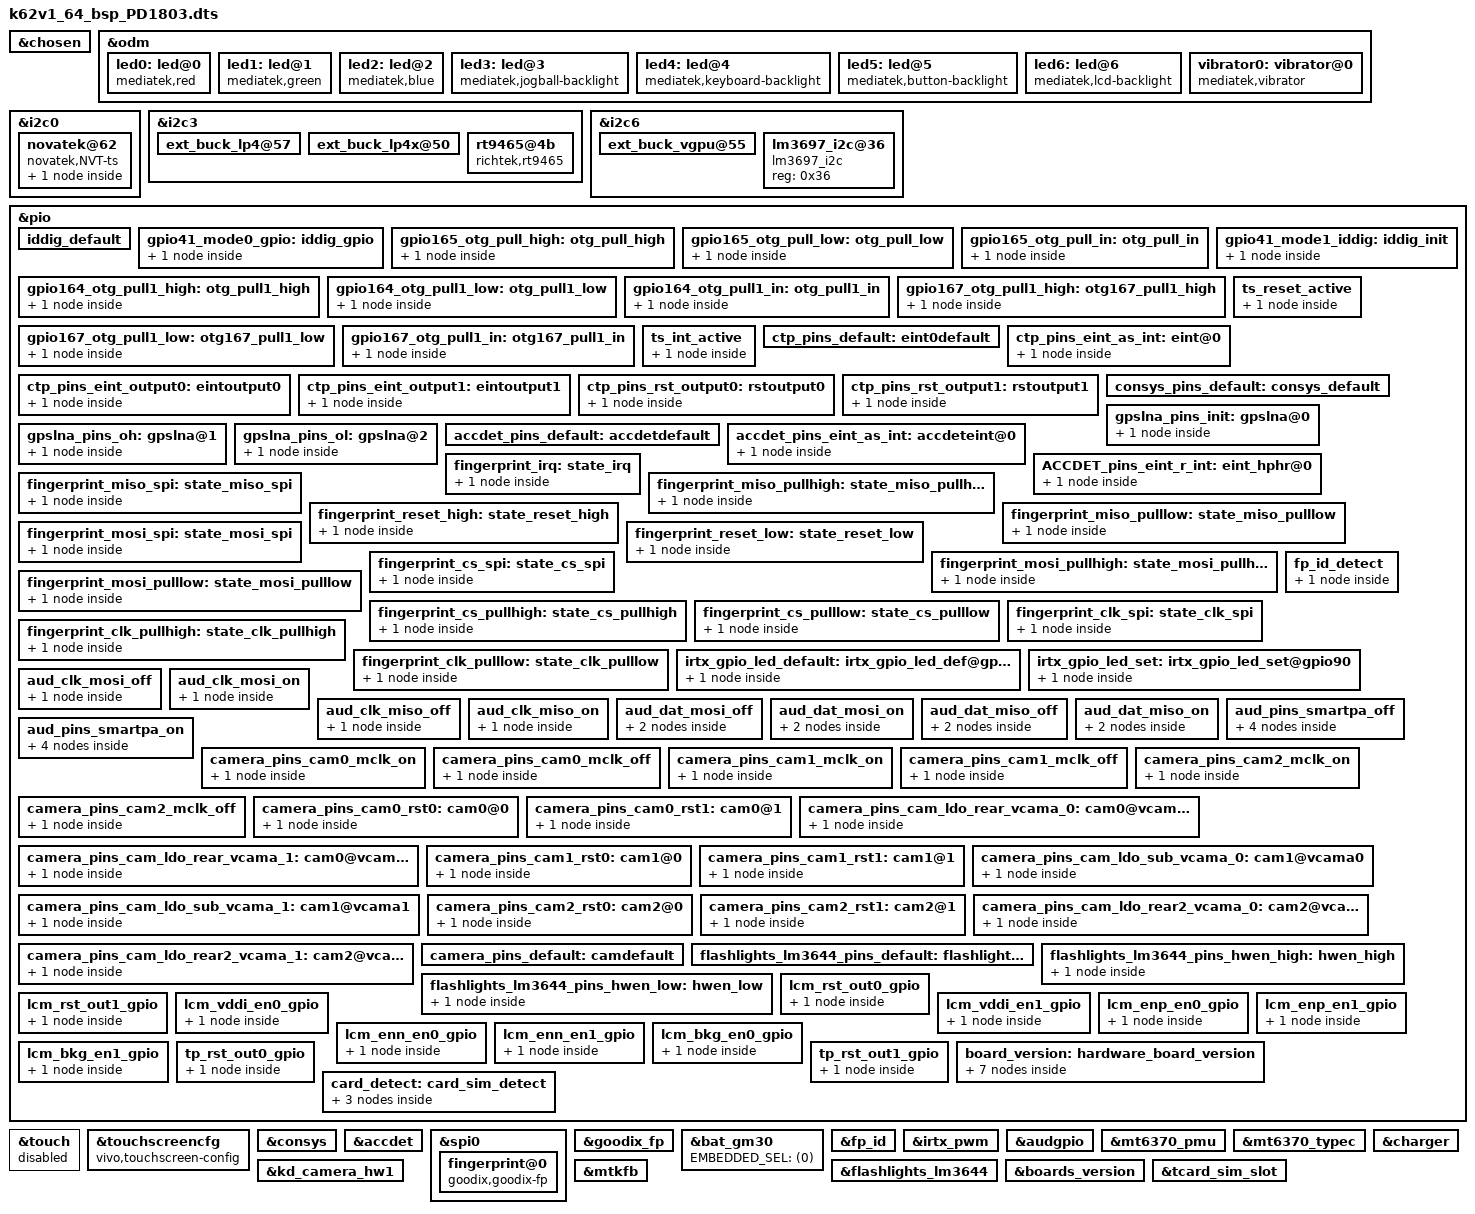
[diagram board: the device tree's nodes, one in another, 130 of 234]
#include <dt-bindings/interrupt-controller/arm-gic.h>
#include <dt-bindings/interrupt-controller/irq.h>
#include <dt-bindings/pinctrl/mt6765-pinfunc.h>
#include <dt-bindings/clock/mt6765-clk.h>

/dts-v1/;
/plugin/;

/* chosen */
&chosen {
	bootargs = "console=tty0 console=ttyS0,921600n1\
root=/dev/ram initrd=0x45000000,0x1000000 loglevel=8 \
androidboot.selinux=permissive androidboot.hardware=mt6765 \
initcall_debug=1 maxcpus=1";

	/* fpga may has no lk, we need to specify display info here */
	/* fb buffer is reserved using this dts by memory node above */
	atag,videolfb-fb_base_h = <0x0>;
	atag,videolfb-fb_base_l = <0x5e605000>;
	atag,videolfb-islcmfound = <1>;
	/* because no lk, so lcm is not inited */
	atag,videolfb-islcm_inited = <0>;
	atag,videolfb-fps= <6000>;
	atag,videolfb-vramSize= <0x017bb000>;
	atag,videolfb-lcmname= "nt35695B_fhd_dsi_cmd_auo_rt5081_drv";
	atag,videolfb-project-name= "PD1803";
};

&odm {
	led0:led@0 {
		compatible = "mediatek,red";
		led_mode = <0>;
		data = <1>;
		pwm_config = <0 0 0 0 0>;
	};
	led1:led@1 {
		compatible = "mediatek,green";
		led_mode = <0>;
		data = <1>;
		pwm_config = <0 0 0 0 0>;
	};
	led2:led@2 {
		compatible = "mediatek,blue";
		led_mode = <0>;
		data = <1>;
		pwm_config = <0 0 0 0 0>;
	};
	led3:led@3 {
		compatible = "mediatek,jogball-backlight";
		led_mode = <0>;
		data = <1>;
		pwm_config = <0 0 0 0 0>;
	};
	led4:led@4 {
		compatible = "mediatek,keyboard-backlight";
		led_mode = <0>;
		data = <1>;
		pwm_config = <0 0 0 0 0>;
	};
	led5:led@5 {
		compatible = "mediatek,button-backlight";
		led_mode = <0>;
		data = <1>;
		pwm_config = <0 0 0 0 0>;
	};
	led6:led@6 {
		compatible = "mediatek,lcd-backlight";
		led_mode = <4>;
		data = <1>;
		pwm_config = <0 0 0 0 0>;
	};
	vibrator0:vibrator@0 {
		compatible = "mediatek,vibrator";
		vib_timer = <25>;
		vib_limit = <9>;
		vib_vol= <9>;
	};
};

&i2c0 {
/*	focaltech@38{ 
	compatible = "focaltech_8006m,fts_8006m";	
	reg = <0x38>;  					
	interrupt-parent = <&pio>;				
	interrupts = <65 0x02>;
	pinctrl-names ="default";
	pinctrl-0 = <&ts_reset_active &ts_int_active>;
//	focaltech,reset-gpio = <&pio 64 0x01>; 
	focaltech,irq-gpio = <&pio 0 0x02>; 	

	focaltech,max-touch-number = <10>;			
	focaltech,display-coords =  <0 0 1080 1920>;	 

//	focaltech,have-key;
	focaltech,key-number = <3>;	
	focaltech,keys = <139 102 158>; 	
	focaltech,key-y-coord = <2000>; 
	focaltech,key-x-coords = <200 600 800>;
};
*/
	novatek@62 {
		compatible = "novatek,NVT-ts";
		reg = <0x62>;
		status = "ok";
		//vdd-supply = <&pm8994_lvs2>;    //VDDIO
		//avdd-supply = <&pm8994_l22>;    //VDD
		//novatek,reset-gpio = <&msm_gpio 102 0x00>;
		novatek,irq-gpio = <&pio 0 0x02>;
		/* MP */
		novatek,mp-support-dt;

		novatek-mp-criteria-5B09@0 {
			#address-cells = <1>;
			#size-cells = <0>;
			compatible = "novatek-mp-criteria-5B09";

			/* MP Config */
			IC_X_CFG_SIZE = <18>;
			IC_Y_CFG_SIZE = <32>;
			IC_KEY_CFG_SIZE = <4>;
			X_Channel = <18>;
			Y_Channel = <32>;
			AIN_X = <0 1 2 3 4 5 6 7 8 9 10 11 12 13 14 15 16 17>;
			AIN_Y = <0 1 2 3 4 5 6 7 8 9 10 11 12 13 14 15 16 17 18 19 20 21 22 23 24 25 26 27 28 29 30 31>;

			AIN_KEY = <0 1 2 0xFF>;
			/* MP Criteria */
			PS_Config_Lmt_Short_Rawdata_P = <
				14008 14008 14008 14008 14008 14008 14008 14008 14008 14008 14008 14008 14008 14008 14008 14008 14008 14008
				14008 14008 14008 14008 14008 14008 14008 14008 14008 14008 14008 14008 14008 14008 14008 14008 14008 14008
				14008 14008 14008 14008 14008 14008 14008 14008 14008 14008 14008 14008 14008 14008 14008 14008 14008 14008
				14008 14008 14008 14008 14008 14008 14008 14008 14008 14008 14008 14008 14008 14008 14008 14008 14008 14008
				14008 14008 14008 14008 14008 14008 14008 14008 14008 14008 14008 14008 14008 14008 14008 14008 14008 14008
				14008 14008 14008 14008 14008 14008 14008 14008 14008 14008 14008 14008 14008 14008 14008 14008 14008 14008
				14008 14008 14008 14008 14008 14008 14008 14008 14008 14008 14008 14008 14008 14008 14008 14008 14008 14008
				14008 14008 14008 14008 14008 14008 14008 14008 14008 14008 14008 14008 14008 14008 14008 14008 14008 14008
				14008 14008 14008 14008 14008 14008 14008 14008 14008 14008 14008 14008 14008 14008 14008 14008 14008 14008
				14008 14008 14008 14008 14008 14008 14008 14008 14008 14008 14008 14008 14008 14008 14008 14008 14008 14008
				14008 14008 14008 14008 14008 14008 14008 14008 14008 14008 14008 14008 14008 14008 14008 14008 14008 14008
				14008 14008 14008 14008 14008 14008 14008 14008 14008 14008 14008 14008 14008 14008 14008 14008 14008 14008
				14008 14008 14008 14008 14008 14008 14008 14008 14008 14008 14008 14008 14008 14008 14008 14008 14008 14008
				14008 14008 14008 14008 14008 14008 14008 14008 14008 14008 14008 14008 14008 14008 14008 14008 14008 14008
				14008 14008 14008 14008 14008 14008 14008 14008 14008 14008 14008 14008 14008 14008 14008 14008 14008 14008
				14008 14008 14008 14008 14008 14008 14008 14008 14008 14008 14008 14008 14008 14008 14008 14008 14008 14008
				14008 14008 14008 14008 14008 14008 14008 14008 14008 14008 14008 14008 14008 14008 14008 14008 14008 14008
				14008 14008 14008 14008 14008 14008 14008 14008 14008 14008 14008 14008 14008 14008 14008 14008 14008 14008
				14008 14008 14008 14008 14008 14008 14008 14008 14008 14008 14008 14008 14008 14008 14008 14008 14008 14008
				14008 14008 14008 14008 14008 14008 14008 14008 14008 14008 14008 14008 14008 14008 14008 14008 14008 14008
				14008 14008 14008 14008 14008 14008 14008 14008 14008 14008 14008 14008 14008 14008 14008 14008 14008 14008
				14008 14008 14008 14008 14008 14008 14008 14008 14008 14008 14008 14008 14008 14008 14008 14008 14008 14008
				14008 14008 14008 14008 14008 14008 14008 14008 14008 14008 14008 14008 14008 14008 14008 14008 14008 14008
				14008 14008 14008 14008 14008 14008 14008 14008 14008 14008 14008 14008 14008 14008 14008 14008 14008 14008
				14008 14008 14008 14008 14008 14008 14008 14008 14008 14008 14008 14008 14008 14008 14008 14008 14008 14008
				14008 14008 14008 14008 14008 14008 14008 14008 14008 14008 14008 14008 14008 14008 14008 14008 14008 14008
				14008 14008 14008 14008 14008 14008 14008 14008 14008 14008 14008 14008 14008 14008 14008 14008 14008 14008
				14008 14008 14008 14008 14008 14008 14008 14008 14008 14008 14008 14008 14008 14008 14008 14008 14008 14008
				14008 14008 14008 14008 14008 14008 14008 14008 14008 14008 14008 14008 14008 14008 14008 14008 14008 14008
				14008 14008 14008 14008 14008 14008 14008 14008 14008 14008 14008 14008 14008 14008 14008 14008 14008 14008
				14008 14008 14008 14008 14008 14008 14008 14008 14008 14008 14008 14008 14008 14008 14008 14008 14008 14008
				14008 14008 14008 14008 14008 14008 14008 14008 14008 14008 14008 14008 14008 14008 14008 14008 14008 14008
				>;

			PS_Config_Lmt_Short_Rawdata_N = <
				11376 11376 11376 11376 11376 11376 11376 11376 11376 11376 11376 11376 11376 11376 11376 11376 11376 11376
				11376 11376 11376 11376 11376 11376 11376 11376 11376 11376 11376 11376 11376 11376 11376 11376 11376 11376
				11376 11376 11376 11376 11376 11376 11376 11376 11376 11376 11376 11376 11376 11376 11376 11376 11376 11376
				11376 11376 11376 11376 11376 11376 11376 11376 11376 11376 11376 11376 11376 11376 11376 11376 11376 11376
				11376 11376 11376 11376 11376 11376 11376 11376 11376 11376 11376 11376 11376 11376 11376 11376 11376 11376
				11376 11376 11376 11376 11376 11376 11376 11376 11376 11376 11376 11376 11376 11376 11376 11376 11376 11376
				11376 11376 11376 11376 11376 11376 11376 11376 11376 11376 11376 11376 11376 11376 11376 11376 11376 11376
				11376 11376 11376 11376 11376 11376 11376 11376 11376 11376 11376 11376 11376 11376 11376 11376 11376 11376
				11376 11376 11376 11376 11376 11376 11376 11376 11376 11376 11376 11376 11376 11376 11376 11376 11376 11376
				11376 11376 11376 11376 11376 11376 11376 11376 11376 11376 11376 11376 11376 11376 11376 11376 11376 11376
				11376 11376 11376 11376 11376 11376 11376 11376 11376 11376 11376 11376 11376 11376 11376 11376 11376 11376
				11376 11376 11376 11376 11376 11376 11376 11376 11376 11376 11376 11376 11376 11376 11376 11376 11376 11376
				11376 11376 11376 11376 11376 11376 11376 11376 11376 11376 11376 11376 11376 11376 11376 11376 11376 11376
				11376 11376 11376 11376 11376 11376 11376 11376 11376 11376 11376 11376 11376 11376 11376 11376 11376 11376
				11376 11376 11376 11376 11376 11376 11376 11376 11376 11376 11376 11376 11376 11376 11376 11376 11376 11376
				11376 11376 11376 11376 11376 11376 11376 11376 11376 11376 11376 11376 11376 11376 11376 11376 11376 11376
				11376 11376 11376 11376 11376 11376 11376 11376 11376 11376 11376 11376 11376 11376 11376 11376 11376 11376
				11376 11376 11376 11376 11376 11376 11376 11376 11376 11376 11376 11376 11376 11376 11376 11376 11376 11376
				11376 11376 11376 11376 11376 11376 11376 11376 11376 11376 11376 11376 11376 11376 11376 11376 11376 11376
				11376 11376 11376 11376 11376 11376 11376 11376 11376 11376 11376 11376 11376 11376 11376 11376 11376 11376
				11376 11376 11376 11376 11376 11376 11376 11376 11376 11376 11376 11376 11376 11376 11376 11376 11376 11376
				11376 11376 11376 11376 11376 11376 11376 11376 11376 11376 11376 11376 11376 11376 11376 11376 11376 11376
				11376 11376 11376 11376 11376 11376 11376 11376 11376 11376 11376 11376 11376 11376 11376 11376 11376 11376
				11376 11376 11376 11376 11376 11376 11376 11376 11376 11376 11376 11376 11376 11376 11376 11376 11376 11376
				11376 11376 11376 11376 11376 11376 11376 11376 11376 11376 11376 11376 11376 11376 11376 11376 11376 11376
				11376 11376 11376 11376 11376 11376 11376 11376 11376 11376 11376 11376 11376 11376 11376 11376 11376 11376
				11376 11376 11376 11376 11376 11376 11376 11376 11376 11376 11376 11376 11376 11376 11376 11376 11376 11376
				11376 11376 11376 11376 11376 11376 11376 11376 11376 11376 11376 11376 11376 11376 11376 11376 11376 11376
				11376 11376 11376 11376 11376 11376 11376 11376 11376 11376 11376 11376 11376 11376 11376 11376 11376 11376
				11376 11376 11376 11376 11376 11376 11376 11376 11376 11376 11376 11376 11376 11376 11376 11376 11376 11376
				11376 11376 11376 11376 11376 11376 11376 11376 11376 11376 11376 11376 11376 11376 11376 11376 11376 11376
				11376 11376 11376 11376 11376 11376 11376 11376 11376 11376 11376 11376 11376 11376 11376 11376 11376 11376
                >;

			

			PS_Config_Lmt_Open_Rawdata_P = <
				65536 3324 3384 3190 3071 2918 65536 65536 65536 65536 65536 65536 2957 3115 3234 3420 3377 65536
                2093 2002 2009 1971 1978 1959 1997 1939 2003 2033 1972 2032 1996 2013 2007 2041 2035 2139
                2077 1994 2000 1973 1979 1970 2006 2005 2063 2099 2043 2045 2010 2017 2011 2035 2031 2116
                2041 1956 1962 1935 1941 1932 1969 1965 2023 2064 2009 2010 1975 1983 1977 2001 1995 2080
                2070 1983 1989 1962 1968 1959 1997 1888 1947 2090 2034 2036 2000 2009 2002 2027 1915 2005
                2072 1984 1991 1964 1970 1959 1997 1996 2055 2088 2032 2033 1997 2006 2000 2026 2021 2110
                2047 1960 1966 1939 1945 1897 1934 1972 2030 2065 2011 2012 1976 1985 1942 1968 2003 2091
                2046 1957 1963 1936 1942 1859 1897 1970 2028 2061 2006 2007 1971 1981 1903 1930 1999 2088
                2083 1995 1998 1972 1976 1968 2005 2008 2065 2092 2036 2037 1999 2010 2006 2032 2028 2120
                2083 1993 1997 1864 1870 1968 2004 2007 2063 2096 2040 2041 1893 1906 2011 2037 2033 2125
                2053 1964 1968 1941 1945 1939 1974 1976 2032 2064 2010 2011 1973 1982 1982 2007 2004 2094
                2059 1968 1972 1949 1953 1944 1979 1981 2038 2065 2009 2011 1976 1986 1983 2008 2005 2096
                2089 1887 1893 1978 1981 1972 2008 2011 2067 2102 1932 1937 2011 2021 2019 2045 2042 2134
                2098 2005 2009 1986 1989 1980 2016 2019 2076 2102 2044 2046 2010 2021 2018 2045 2042 2135
                2062 1973 1977 1952 1955 1945 1981 1984 2040 2076 2023 2024 1986 1998 1995 2022 2020 2112
                1950 1973 1977 1952 1955 1945 1982 1984 2040 1958 2018 2020 1982 1993 1992 2018 2016 2108
                2066 1977 1980 1956 1959 1950 1986 1988 2044 2074 2019 2020 1983 1994 1993 2020 2018 2111
                2075 1987 1986 1963 1966 1957 1993 1994 2051 2080 2023 2025 1988 2000 1998 2025 2026 2117
                2105 2022 2014 1990 1994 1983 2021 1977 2034 2111 2055 2057 2018 2030 2029 2056 2020 2104
                2107 2023 2016 1992 1996 1986 2023 2024 2082 2113 2057 2059 2020 2032 2031 2058 2068 2154
                2070 1989 1980 1958 1961 1950 1988 1989 2046 2081 2025 2027 1989 2002 1999 2025 2037 2121
                2078 1996 1991 1964 1968 1911 1950 1997 2053 2081 2025 2028 1989 2002 1953 1983 2036 2121
                2115 2031 2033 2002 2003 1992 2031 2031 2090 2119 2062 2065 2025 2037 2039 2074 2073 2160
                2117 2033 2036 2011 2003 1993 2033 2033 2092 2123 2065 2070 2028 2041 2051 2079 2077 2164
                2084 2002 2005 1936 1929 1964 2002 2002 2059 2090 2034 2039 1951 1967 2020 2048 2044 2132
                2085 2003 2007 1983 1975 1964 2004 2003 2061 2087 2030 2037 1994 2009 2017 2045 2041 2129
                2121 2034 2038 2016 2012 1996 2037 2034 2092 2120 2061 2067 2025 2047 2051 2080 2076 2167
                2125 1992 1998 2019 2024 2000 2041 2037 2094 2130 2025 2031 2033 2064 2059 2088 2084 2176
                2093 2009 2013 1990 1994 1971 2011 2009 2065 2094 2037 2044 2001 2029 2025 2054 2051 2140
                2106 2056 2059 2037 2040 2020 2061 2059 2114 2104 2082 2090 2048 2075 2070 2096 2094 2184
                2133 2053 2060 2035 2041 2018 2064 2059 2119 2129 2083 2095 2049 2079 2072 2102 2093 2195
                1866 2268 2271 2239 2245 2220 2273 2264 2346 2378 2298 2314 2259 2291 2284 2323 2318 1917
            >;

			PS_Config_Lmt_Open_Rawdata_N = <
                0 1425 1450 1367 1316 1251 0 0 0 0 0 0 1267 1335 1386 1466 1447 0
                897 858 861 845 848 840 856 831 858 871 845 871 855 863 860 875 872 917
                890 854 857 845 848 844 860 859 884 900 876 877 862 864 862 872 870 907
                875 838 841 829 832 828 844 842 867 884 861 862 846 850 847 858 855 892
                887 850 853 841 843 839 856 809 834 896 872 873 857 861 858 869 821 859
                888 850 853 842 844 840 856 856 881 895 871 871 856 860 857 868 866 904
                877 840 843 831 834 813 829 845 870 885 862 862 847 851 832 844 858 896
                877 839 841 830 832 797 813 844 869 883 860 860 845 849 815 827 857 895
                893 855 856 845 847 843 859 860 885 897 873 873 857 861 860 871 869 909
                893 854 856 799 801 844 859 860 884 898 874 875 811 817 862 873 871 911
                880 842 843 832 833 831 846 847 871 885 861 862 845 850 850 860 859 897
                883 844 845 835 837 833 848 849 873 885 861 862 847 851 850 860 859 898
                895 809 811 848 849 845 861 862 886 901 828 830 862 866 865 876 875 915
                899 859 861 851 852 848 864 865 890 901 876 877 861 866 865 876 875 915
                884 846 847 837 838 834 849 850 874 890 867 867 851 856 855 866 866 905
                836 846 847 837 838 834 850 850 874 839 865 866 849 854 854 865 864 904
                885 847 848 838 840 836 851 852 876 889 865 866 850 855 854 866 865 905
                889 851 851 841 843 839 854 855 879 891 867 868 852 857 856 868 868 907
                902 867 863 853 854 850 866 847 872 905 881 881 865 870 869 881 866 902
                903 867 864 854 855 851 867 867 892 906 882 882 866 871 870 882 886 923
                887 852 849 839 840 836 852 853 877 892 868 869 852 858 857 868 873 909
                890 855 853 842 843 819 836 856 880 892 868 869 852 858 837 850 873 909
                907 870 871 858 858 854 870 871 896 908 884 885 868 873 874 889 889 926
                907 871 873 862 858 854 871 871 896 910 885 887 869 875 879 891 890 928
                893 858 859 830 827 842 858 858 883 896 872 874 836 843 866 878 876 914
                894 859 860 850 846 842 859 858 883 895 870 873 855 861 864 877 875 912
                909 872 873 864 862 856 873 872 896 908 883 886 868 877 879 891 890 929
                911 854 856 865 867 857 875 873 898 913 868 870 871 884 882 895 893 933
                897 861 863 853 855 845 862 861 885 897 873 876 858 870 868 880 879 917
                903 881 882 873 874 866 883 883 906 902 892 896 878 889 887 898 897 936
                914 880 883 872 875 865 885 882 908 912 893 898 878 891 888 901 897 941
                800 972 973 960 962 952 974 970 1005 1019 985 992 968 982 979 995 994 822
            >;

			PS_Config_Lmt_FW_Rawdata_P = <
                852 841 854 858 873 855 843 852 851 853 851 849 855 864 868 869 844 839
                841 831 837 838 844 835 845 837 845 831 839 842 845 832 848 840 845 830
                847 840 837 838 834 831 844 831 847 840 841 844 862 845 850 846 850 842
                830 844 840 834 840 833 832 840 839 848 843 836 846 830 838 834 842 844
                820 831 831 831 844 830 850 845 842 837 849 836 852 837 849 843 840 848
                842 837 835 830 852 840 846 840 850 843 851 847 858 839 839 849 840 843
                831 832 841 834 835 834 834 832 838 834 850 839 845 835 846 831 846 843
                849 833 835 831 837 842 842 834 828 845 849 840 849 837 851 836 846 844
                831 824 839 837 841 839 847 835 837 839 850 838 853 838 848 841 853 845
                828 850 833 845 826 828 830 829 827 835 840 837 842 837 854 840 845 843
                829 835 834 834 848 842 835 834 845 840 860 844 852 842 840 832 844 832
                839 831 834 838 834 832 846 840 840 837 851 834 850 838 843 837 845 852
                851 844 837 827 841 841 834 834 836 843 856 834 849 839 842 824 850 841
                832 832 834 836 833 826 842 832 836 823 840 838 853 838 852 837 836 842
                830 831 838 837 838 828 834 838 840 833 853 841 848 835 834 823 853 843
                844 831 849 836 836 822 849 826 847 833 849 840 853 838 855 828 853 834
                820 839 843 844 837 827 844 835 843 819 839 835 851 834 850 829 841 833
                835 831 836 831 841 837 850 835 830 833 837 828 854 819 850 836 851 839
                818 836 842 839 833 824 844 828 826 840 855 837 844 831 845 832 835 838
                832 835 845 834 828 825 839 825 839 833 848 838 850 834 845 838 829 833
                838 833 830 827 838 835 839 834 834 818 852 826 842 832 850 824 838 839
                827 832 826 825 828 829 845 840 839 826 854 834 853 836 848 831 841 834
                843 831 837 834 846 836 836 842 835 827 844 837 850 840 844 827 834 840
                831 835 847 833 828 829 834 831 829 831 851 831 849 834 843 834 846 835
                838 830 830 826 852 843 839 839 838 841 850 838 849 831 841 839 854 847
                830 838 841 840 835 829 847 836 836 833 847 833 846 836 844 825 840 841
                825 830 837 834 838 826 844 836 830 833 850 826 849 838 843 834 836 838
                837 832 844 841 837 833 835 830 838 833 848 826 842 834 842 834 854 837
                836 832 830 841 833 836 838 832 832 821 848 838 849 831 854 832 844 834
                836 835 836 844 843 839 837 839 836 829 840 828 844 824 856 830 845 844
                829 838 838 842 836 817 840 841 845 838 854 832 852 832 843 828 840 845
                836 816 837 832 831 838 834 827 835 830 834 836 842 827 840 834 830 830
                >;

			PS_Config_Lmt_FW_Rawdata_N = <
				365 361 366 368 374 366 361 365 365 365 365 364 366 370 372 372 362 359
                360 356 359 359 362 358 362 359 362 356 359 361 362 357 364 360 362 356
                363 360 359 359 358 356 362 356 363 360 360 362 369 362 364 363 364 361
                356 362 360 358 360 357 357 360 360 363 361 358 362 356 359 358 361 362
                352 356 356 356 362 356 364 362 361 359 364 358 365 359 364 361 360 364
                361 359 358 356 365 360 363 360 364 361 365 363 368 360 360 364 360 361
                356 357 360 357 358 357 357 356 359 358 364 360 362 358 362 356 362 361
                364 357 358 356 359 361 361 357 355 362 364 360 364 359 365 358 363 362
                356 353 360 359 361 359 363 358 359 360 364 359 365 359 363 360 366 362
                355 364 357 362 354 355 356 355 354 358 360 359 361 359 366 360 362 361
                355 358 357 357 363 361 358 358 362 360 368 362 365 361 360 356 362 357
                360 356 357 359 358 356 363 360 360 359 365 357 364 359 361 359 362 365
                365 362 359 355 360 360 358 357 358 361 367 358 364 360 361 353 364 360
                357 357 357 358 357 354 361 357 358 353 360 359 366 359 365 359 358 361
                356 356 359 359 359 355 358 359 360 357 366 360 363 358 358 353 366 361
                362 356 364 358 358 352 364 354 363 357 364 360 365 359 366 355 365 357
                351 360 361 362 359 354 362 358 361 351 360 358 365 358 364 355 360 357
                358 356 358 356 360 359 364 358 356 357 359 355 366 351 364 358 365 360
                351 358 361 359 357 353 362 355 354 360 366 359 362 356 362 356 358 359
                357 358 362 357 355 353 360 354 359 357 363 359 364 358 362 359 355 357
                359 357 356 354 359 358 360 357 358 351 365 354 361 357 364 353 359 360
                354 357 354 354 355 355 362 360 359 354 366 357 365 358 363 356 360 357
                361 356 359 357 363 358 358 361 358 355 362 359 364 360 362 355 358 360
                356 358 363 357 355 355 357 356 355 356 365 356 364 357 361 357 362 358
                359 356 356 354 365 361 359 359 359 360 364 359 364 356 360 360 366 363
                356 359 360 360 358 355 363 358 358 357 363 357 362 358 362 354 360 361
                354 356 359 357 359 354 362 358 356 357 364 354 364 359 361 357 358 359
                359 356 362 361 359 357 358 356 359 357 364 354 361 357 361 358 366 359
                358 356 356 360 357 358 359 356 357 352 364 359 364 356 366 357 362 357
                358 358 358 362 361 360 359 359 358 355 360 355 362 353 367 356 362 362
                355 359 359 361 358 350 360 361 362 359 366 357 365 357 361 355 360 362
                358 350 359 356 356 359 357 354 358 356 357 358 361 354 360 358 356 356
                >;

			PS_Config_Lmt_FW_CC_P = <
				512 138 175 179 182 174 512 512 512 512 512 512 173 181 178 171 137 512
                132 129 129 130 130 131 131 132 134 134 132 132 130 130 129 129 128 131
                130 127 127 127 128 128 127 128 130 130 128 128 128 128 127 126 126 129
                132 128 129 129 130 130 129 130 132 133 131 131 131 131 130 130 129 132
                132 129 129 129 130 130 130 130 132 133 131 130 130 130 129 129 129 132
                133 130 130 130 131 131 130 131 133 133 130 130 130 130 129 129 129 132
                132 129 129 129 130 130 130 130 132 133 131 131 131 131 130 130 130 133
                132 129 129 129 130 130 130 130 132 134 131 131 131 131 130 130 130 133
                133 130 131 131 131 131 131 131 134 134 131 131 131 131 130 130 130 133
                133 130 130 130 131 131 131 131 133 134 131 131 131 131 130 130 130 133
                132 129 130 130 130 130 130 130 132 134 132 132 132 132 131 131 131 134
                133 130 130 130 131 131 130 131 133 134 132 132 132 132 131 131 131 134
                134 131 131 131 132 132 131 132 134 135 133 133 133 133 132 132 131 135
                134 131 132 131 132 132 132 132 135 135 133 132 132 132 132 132 131 134
                134 130 131 131 131 131 131 132 134 136 133 133 133 133 132 132 132 135
                134 130 131 130 131 131 131 131 134 135 133 133 133 133 132 132 132 135
                134 131 131 131 132 132 131 132 134 135 133 133 133 133 132 132 132 136
                135 132 132 132 133 133 132 133 135 135 133 133 133 133 132 132 132 135
                135 131 132 132 132 132 132 132 135 137 134 134 134 134 134 134 134 137
                135 131 132 132 133 133 132 133 135 136 134 134 134 134 133 133 133 137
                135 131 131 131 132 132 132 132 134 136 133 133 133 133 132 133 132 136
                135 132 132 132 133 133 132 132 135 135 133 133 133 133 132 133 132 136
                135 131 132 132 132 132 132 132 135 136 134 134 134 134 133 133 133 137
                136 132 132 132 133 133 132 133 135 137 134 134 134 134 133 134 134 137
                136 132 133 132 133 133 133 133 135 136 134 134 134 134 133 133 133 137
                136 132 132 132 133 133 132 133 135 136 133 133 133 133 133 133 133 137
                136 132 132 131 132 132 132 132 134 135 133 133 133 133 133 133 133 137
                136 132 132 132 133 133 133 132 134 136 134 133 133 134 133 133 134 138
                136 132 132 132 132 133 132 132 135 135 133 132 133 132 132 132 133 137
                135 131 131 131 131 132 132 132 134 133 131 131 131 131 130 130 130 134
                137 132 133 132 133 134 134 134 136 136 134 133 134 134 133 133 133 137
                129 133 132 131 132 132 132 132 135 135 132 132 132 132 132 133 132 129
                >;

			PS_Config_Lmt_FW_CC_N = <
				0 80 80 80 80 80 0 0 0 0 0 0 80 80 80 80 80 0
                80 80 80 80 80 80 80 80 80 80 80 80 80 80 80 80 80 80
                80 80 80 80 80 80 80 80 80 80 80 80 80 80 80 80 80 80
                80 80 80 80 80 80 80 80 80 80 80 80 80 80 80 80 80 80
                80 80 80 80 80 80 80 80 80 80 80 80 80 80 80 80 80 80
                80 80 80 80 80 80 80 80 80 80 80 80 80 80 80 80 80 80
                80 80 80 80 80 80 80 80 80 80 80 80 80 80 80 80 80 80
                80 80 80 80 80 80 80 80 80 80 80 80 80 80 80 80 80 80
                80 80 80 80 80 80 80 80 80 80 80 80 80 80 80 80 80 80
                80 80 80 80 80 80 80 80 80 80 80 80 80 80 80 80 80 80
                80 80 80 80 80 80 80 80 80 80 80 80 80 80 80 80 80 80
                80 80 80 80 80 80 80 80 80 80 80 80 80 80 80 80 80 80
                80 80 80 80 80 80 80 80 80 80 80 80 80 80 80 80 80 80
                80 80 80 80 80 80 80 80 80 80 80 80 80 80 80 80 80 80
                80 80 80 80 80 80 80 80 80 80 80 80 80 80 80 80 80 80
                80 80 80 80 80 80 80 80 80 80 80 80 80 80 80 80 80 80
                80 80 80 80 80 80 80 80 80 80 80 80 80 80 80 80 80 80
                80 80 80 80 80 80 80 80 80 80 80 80 80 80 80 80 80 80
                80 80 80 80 80 80 80 80 80 80 80 80 80 80 80 80 80 80
                80 80 80 80 80 80 80 80 80 80 80 80 80 80 80 80 80 80
                80 80 80 80 80 80 80 80 80 80 80 80 80 80 80 80 80 80
                80 80 80 80 80 80 80 80 80 80 80 80 80 80 80 80 80 80
                80 80 80 80 80 80 80 80 80 80 80 80 80 80 80 80 80 80
                80 80 80 80 80 80 80 80 80 80 80 80 80 80 80 80 80 80
                80 80 80 80 80 80 80 80 80 80 80 80 80 80 80 80 80 80
                80 80 80 80 80 80 80 80 80 80 80 80 80 80 80 80 80 80
                80 80 80 80 80 80 80 80 80 80 80 80 80 80 80 80 80 80
                80 80 80 80 80 80 80 80 80 80 80 80 80 80 80 80 80 80
                80 80 80 80 80 80 80 80 80 80 80 80 80 80 80 80 80 80
                80 80 80 80 80 80 80 80 80 80 80 80 80 80 80 80 80 80
                80 80 80 80 80 80 80 80 80 80 80 80 80 80 80 80 80 80
                80 80 80 80 80 80 80 80 80 80 80 80 80 80 80 80 80 80
		        >;

			

			PS_Config_Lmt_FW_Diff_P = <
				35 35 35 35 35 35 35 35 35 35 35 35 35 35 35 35 35 35
				35 35 35 35 35 35 35 35 35 35 35 35 35 35 35 35 35 35
				35 35 35 35 35 35 35 35 35 35 35 35 35 35 35 35 35 35
				35 35 35 35 35 35 35 35 35 35 35 35 35 35 35 35 35 35
				35 35 35 35 35 35 35 35 35 35 35 35 35 35 35 35 35 35
				35 35 35 35 35 35 35 35 35 35 35 35 35 35 35 35 35 35
				35 35 35 35 35 35 35 35 35 35 35 35 35 35 35 35 35 35
				35 35 35 35 35 35 35 35 35 35 35 35 35 35 35 35 35 35
				35 35 35 35 35 35 35 35 35 35 35 35 35 35 35 35 35 35
				35 35 35 35 35 35 35 35 35 35 35 35 35 35 35 35 35 35
				35 35 35 35 35 35 35 35 35 35 35 35 35 35 35 35 35 35
				35 35 35 35 35 35 35 35 35 35 35 35 35 35 35 35 35 35
				35 35 35 35 35 35 35 35 35 35 35 35 35 35 35 35 35 35
				35 35 35 35 35 35 35 35 35 35 35 35 35 35 35 35 35 35
				35 35 35 35 35 35 35 35 35 35 35 35 35 35 35 35 35 35
				35 35 35 35 35 35 35 35 35 35 35 35 35 35 35 35 35 35
				35 35 35 35 35 35 35 35 35 35 35 35 35 35 35 35 35 35
				35 35 35 35 35 35 35 35 35 35 35 35 35 35 35 35 35 35
				35 35 35 35 35 35 35 35 35 35 35 35 35 35 35 35 35 35
				35 35 35 35 35 35 35 35 35 35 35 35 35 35 35 35 35 35
				35 35 35 35 35 35 35 35 35 35 35 35 35 35 35 35 35 35
				35 35 35 35 35 35 35 35 35 35 35 35 35 35 35 35 35 35
				35 35 35 35 35 35 35 35 35 35 35 35 35 35 35 35 35 35
				35 35 35 35 35 35 35 35 35 35 35 35 35 35 35 35 35 35
				35 35 35 35 35 35 35 35 35 35 35 35 35 35 35 35 35 35
				35 35 35 35 35 35 35 35 35 35 35 35 35 35 35 35 35 35
				35 35 35 35 35 35 35 35 35 35 35 35 35 35 35 35 35 35
				35 35 35 35 35 35 35 35 35 35 35 35 35 35 35 35 35 35
				35 35 35 35 35 35 35 35 35 35 35 35 35 35 35 35 35 35
				35 35 35 35 35 35 35 35 35 35 35 35 35 35 35 35 35 35
				35 35 35 35 35 35 35 35 35 35 35 35 35 35 35 35 35 35
				35 35 35 35 35 35 35 35 35 35 35 35 35 35 35 35 35 35
				35 35 35>;

			PS_Config_Lmt_FW_Diff_N = <
				(-35) (-35) (-35) (-35) (-35) (-35) (-35) (-35) (-35) (-35) (-35) (-35) (-35) (-35) (-35) (-35) (-35) (-35)
				(-35) (-35) (-35) (-35) (-35) (-35) (-35) (-35) (-35) (-35) (-35) (-35) (-35) (-35) (-35) (-35) (-35) (-35)
				(-35) (-35) (-35) (-35) (-35) (-35) (-35) (-35) (-35) (-35) (-35) (-35) (-35) (-35) (-35) (-35) (-35) (-35)
				(-35) (-35) (-35) (-35) (-35) (-35) (-35) (-35) (-35) (-35) (-35) (-35) (-35) (-35) (-35) (-35) (-35) (-35)
				(-35) (-35) (-35) (-35) (-35) (-35) (-35) (-35) (-35) (-35) (-35) (-35) (-35) (-35) (-35) (-35) (-35) (-35)
				(-35) (-35) (-35) (-35) (-35) (-35) (-35) (-35) (-35) (-35) (-35) (-35) (-35) (-35) (-35) (-35) (-35) (-35)
				(-35) (-35) (-35) (-35) (-35) (-35) (-35) (-35) (-35) (-35) (-35) (-35) (-35) (-35) (-35) (-35) (-35) (-35)
				(-35) (-35) (-35) (-35) (-35) (-35) (-35) (-35) (-35) (-35) (-35) (-35) (-35) (-35) (-35) (-35) (-35) (-35)
				(-35) (-35) (-35) (-35) (-35) (-35) (-35) (-35) (-35) (-35) (-35) (-35) (-35) (-35) (-35) (-35) (-35) (-35)
				(-35) (-35) (-35) (-35) (-35) (-35) (-35) (-35) (-35) (-35) (-35) (-35) (-35) (-35) (-35) (-35) (-35) (-35)
				(-35) (-35) (-35) (-35) (-35) (-35) (-35) (-35) (-35) (-35) (-35) (-35) (-35) (-35) (-35) (-35) (-35) (-35)
				(-35) (-35) (-35) (-35) (-35) (-35) (-35) (-35) (-35) (-35) (-35) (-35) (-35) (-35) (-35) (-35) (-35) (-35)
				(-35) (-35) (-35) (-35) (-35) (-35) (-35) (-35) (-35) (-35) (-35) (-35) (-35) (-35) (-35) (-35) (-35) (-35)
				(-35) (-35) (-35) (-35) (-35) (-35) (-35) (-35) (-35) (-35) (-35) (-35) (-35) (-35) (-35) (-35) (-35) (-35)
				(-35) (-35) (-35) (-35) (-35) (-35) (-35) (-35) (-35) (-35) (-35) (-35) (-35) (-35) (-35) (-35) (-35) (-35)
				(-35) (-35) (-35) (-35) (-35) (-35) (-35) (-35) (-35) (-35) (-35) (-35) (-35) (-35) (-35) (-35) (-35) (-35)
				(-35) (-35) (-35) (-35) (-35) (-35) (-35) (-35) (-35) (-35) (-35) (-35) (-35) (-35) (-35) (-35) (-35) (-35)
				(-35) (-35) (-35) (-35) (-35) (-35) (-35) (-35) (-35) (-35) (-35) (-35) (-35) (-35) (-35) (-35) (-35) (-35)
				(-35) (-35) (-35) (-35) (-35) (-35) (-35) (-35) (-35) (-35) (-35) (-35) (-35) (-35) (-35) (-35) (-35) (-35)
				(-35) (-35) (-35) (-35) (-35) (-35) (-35) (-35) (-35) (-35) (-35) (-35) (-35) (-35) (-35) (-35) (-35) (-35)
				(-35) (-35) (-35) (-35) (-35) (-35) (-35) (-35) (-35) (-35) (-35) (-35) (-35) (-35) (-35) (-35) (-35) (-35)
				(-35) (-35) (-35) (-35) (-35) (-35) (-35) (-35) (-35) (-35) (-35) (-35) (-35) (-35) (-35) (-35) (-35) (-35)
				(-35) (-35) (-35) (-35) (-35) (-35) (-35) (-35) (-35) (-35) (-35) (-35) (-35) (-35) (-35) (-35) (-35) (-35)
				(-35) (-35) (-35) (-35) (-35) (-35) (-35) (-35) (-35) (-35) (-35) (-35) (-35) (-35) (-35) (-35) (-35) (-35)
				(-35) (-35) (-35) (-35) (-35) (-35) (-35) (-35) (-35) (-35) (-35) (-35) (-35) (-35) (-35) (-35) (-35) (-35)
				(-35) (-35) (-35) (-35) (-35) (-35) (-35) (-35) (-35) (-35) (-35) (-35) (-35) (-35) (-35) (-35) (-35) (-35)
				(-35) (-35) (-35) (-35) (-35) (-35) (-35) (-35) (-35) (-35) (-35) (-35) (-35) (-35) (-35) (-35) (-35) (-35)
				(-35) (-35) (-35) (-35) (-35) (-35) (-35) (-35) (-35) (-35) (-35) (-35) (-35) (-35) (-35) (-35) (-35) (-35)
				(-35) (-35) (-35) (-35) (-35) (-35) (-35) (-35) (-35) (-35) (-35) (-35) (-35) (-35) (-35) (-35) (-35) (-35)
				(-35) (-35) (-35) (-35) (-35) (-35) (-35) (-35) (-35) (-35) (-35) (-35) (-35) (-35) (-35) (-35) (-35) (-35)
				(-35) (-35) (-35) (-35) (-35) (-35) (-35) (-35) (-35) (-35) (-35) (-35) (-35) (-35) (-35) (-35) (-35) (-35)
				(-35) (-35) (-35) (-35) (-35) (-35) (-35) (-35) (-35) (-35) (-35) (-35) (-35) (-35) (-35) (-35) (-35) (-35)
				(-35) (-35) (-35)>;

			PS_Config_Diff_Test_Frame = <50>;
		};
	};
};

&i2c3 {
	ext_buck_lp4@57 {
		regulator-name ="ext_buck_vdd2";
		regulator-min-microvolt = <300000>;
		regulator-max-microvolt = <1300000>;
		vsel_pin = <0>;
	};

	ext_buck_lp4x@50 {
		regulator-name ="ext_buck_vddq";
		regulator-min-microvolt = <300000>;
		regulator-max-microvolt = <1300000>;
		vsel_pin = <1>;
	};
};

&i2c6 {
	ext_buck_vgpu@55 {
		regulator-name ="ext_buck_vgpu";
		regulator-min-microvolt = <300000>;
		regulator-max-microvolt = <1300000>;
		vsel_pin = <2>;
	};
};

/*add by wutianwen for usbid second detection*/
&pio {
	iddig_default: iddig_default {
	};

	gpio41_mode0_gpio: iddig_gpio {
		pins_cmd_dat {
			pinmux = <PINMUX_GPIO41__FUNC_GPIO41>;
			input-enable;
			slew-rate = <0>;
			/*bias-pull-up = <00>;*/
			bias-disable;
		};
	};

	gpio165_otg_pull_high: otg_pull_high {
		pins_cmd_dat {
			pinmux = <PINMUX_GPIO165__FUNC_GPIO165>;
			slew-rate = <1>;
			bias-pull-up = <11>;
			output-high;
		};
	};
	gpio165_otg_pull_low: otg_pull_low {
		pins_cmd_dat {
			pinmux = <PINMUX_GPIO165__FUNC_GPIO165>;
			slew-rate = <1>;
			output-low;
		};
	};
	gpio165_otg_pull_in: otg_pull_in {
		pins_cmd_dat {
			pinmux = <PINMUX_GPIO165__FUNC_GPIO165>;
			input-enable;
			slew-rate = <0>;
			/*bias-pull-up = <00>;*/
			bias-disable;
		};
	};

	gpio164_otg_pull1_high: otg_pull1_high {
		pins_cmd_dat {
			pinmux = <PINMUX_GPIO164__FUNC_GPIO164>;
			slew-rate = <1>;
			bias-pull-up = <11>;
			output-high;
		};
	};
	gpio164_otg_pull1_low: otg_pull1_low {
		pins_cmd_dat {
			pinmux = <PINMUX_GPIO164__FUNC_GPIO164>;
			slew-rate = <1>;
			output-low;
		};
	};
	gpio164_otg_pull1_in: otg_pull1_in {
		pins_cmd_dat {
			pinmux = <PINMUX_GPIO164__FUNC_GPIO164>;
			input-enable;
			slew-rate = <0>;
			/*bias-pull-up = <00>;*/
			bias-disable;
		};
	};
	
	gpio41_mode1_iddig: iddig_init {
		pins_cmd_dat {
			pinmux = <PINMUX_GPIO41__FUNC_IDDIG>;
			input-enable;
			slew-rate = <0>;
			/*bias-pull-up = <00>;*/
			bias-disable;
		};
	};
	
	gpio167_otg_pull1_high: otg167_pull1_high {
		pins_cmd_dat {
			pinmux = <PINMUX_GPIO167__FUNC_GPIO167>;
			slew-rate = <1>;
			bias-pull-up = <11>;
			output-high;
		};
	};
	gpio167_otg_pull1_low: otg167_pull1_low {
		pins_cmd_dat {
			pinmux = <PINMUX_GPIO167__FUNC_GPIO167>;
			slew-rate = <1>;
			output-low;
		};
	};
	gpio167_otg_pull1_in: otg167_pull1_in {
		pins_cmd_dat {
			pinmux = <PINMUX_GPIO167__FUNC_GPIO167>;
			input-enable;
			slew-rate = <0>;
			/*bias-pull-up = <00>;*/
			bias-disable;
		};
	};
	
};

/* TOUCH start */
&touch {
	tpd-resolution = <1080 1920>;
	use-tpd-button = <0>;
	tpd-key-num = <3>;
	tpd-key-local= <139 172 158 0>;
	tpd-key-dim-local = <90 883 100 40 230
				 883 100 40 370 883 100 40 0 0 0 0>;
	tpd-max-touch-num = <5>;
	tpd-filter-enable = <0>;
	tpd-filter-pixel-density = <146>;
	tpd-filter-custom-prameters = <0 0 0 0 0 0 0 0 0 0 0 0>;
	tpd-filter-custom-speed = <0 0 0>;
	pinctrl-names = "default", "state_eint_as_int", "state_eint_output0",
		"state_eint_output1", "state_rst_output0", "state_rst_output1";
	pinctrl-0 = <&ctp_pins_default>;
	pinctrl-1 = <&ctp_pins_eint_as_int>;
	pinctrl-2 = <&ctp_pins_eint_output0>;
	pinctrl-3 = <&ctp_pins_eint_output1>;
	pinctrl-4 = <&ctp_pins_rst_output0>;
	pinctrl-5 = <&ctp_pins_rst_output1>;
	status = "disableld";
};
&pio {
	ts_reset_active: ts_reset_active {
		pins_cmd_dat {
			pinmux = <PINMUX_GPIO10__FUNC_GPIO10>;
			slew-rate = <1>;
			output-high;
			bias-disable;
		};
	};
	ts_int_active: ts_int_active {
		pins_cmd_dat {
			pinmux = <PINMUX_GPIO0__FUNC_GPIO0>;
			slew-rate = <0>;
			input-enable;
			bias-disable;
		};
	};
	ctp_pins_default: eint0default {
	};
	ctp_pins_eint_as_int: eint@0 {
		pins_cmd_dat {
			/*pinmux = <PINMUX_GPIO0__FUNC_GPIO0>;*/
			slew-rate = <0>;
			bias-disable;
		};
	};
	ctp_pins_eint_output0: eintoutput0 {
		pins_cmd_dat {
			/*pinmux = <PINMUX_GPIO0__FUNC_GPIO0>;*/
			slew-rate = <1>;
			output-low;
		};
	};
	ctp_pins_eint_output1: eintoutput1 {
		pins_cmd_dat {
			/*pinmux = <PINMUX_GPIO0__FUNC_GPIO0>;*/
			slew-rate = <1>;
			output-high;
		};
	};
	ctp_pins_rst_output0: rstoutput0 {
		pins_cmd_dat {
			/*pinmux = <PINMUX_GPIO174__FUNC_GPIO174>;*/
			slew-rate = <1>;
			output-low;
		};
	};
	ctp_pins_rst_output1: rstoutput1 {
		pins_cmd_dat {
			/*pinmux = <PINMUX_GPIO174__FUNC_GPIO174>;*/
			slew-rate = <1>;
			output-high;
		};
	};
};
/* TOUCH end */

&touchscreencfg { /* vivo ts configure */
	   compatible = "vivo,touchscreen-config";
	   vivo,ts-product-name="PD1803";
   vivo,use-ic-list="nt36525";
	   vivo,ts_vdd_mode="gpio_mode"; /*regulator_mode or gpio_mode*/

	   
	   /*----- function set BEG ---- */
	   vivo,ts-gloves-mode=<0>;
	   vivo,ts-large-obj-suppression=<1>;
	   vivo,ts-dclick-wake=<1>;
	   vivo,ts-gesture-mode=<1>; /*1=sold in native,2=sold in abroad,3...etc=for custom extensive*/
	   vivo,ts-custom-gesture=<0>;
	   vivo,ts-module-id-methods=<2>;/*0=by IC id,1=gpio,2=by LCD ID 3=...etc=for custom extensive*/
	   vivo,ts-fw-upgrade-lcd-referrence=<0>;
	   vivo,ts-anti-esd=<1>;
	   vivo,ts-charger-conn-judge=<1>;
	   vivo,ts-module-smt-mode=<1>; /* 0=COB,1=COF */
	   /*----- function set END ---- */
  status = "okay";
	};


/* CONSYS GPIO standardization */
&pio {
	consys_pins_default: consys_default {
	};
	gpslna_pins_init: gpslna@0 {
		pins_cmd_dat {
			pinmux = <PINMUX_GPIO91__FUNC_GPIO91>;
			slew-rate = <0>;
			bias-disable;
			output-low;
		};
	};
	gpslna_pins_oh: gpslna@1 {
		pins_cmd_dat {
			pinmux = <PINMUX_GPIO91__FUNC_GPIO91>;
			slew-rate = <1>;
			output-high;
		};
	};
	gpslna_pins_ol: gpslna@2 {
		pins_cmd_dat {
			pinmux = <PINMUX_GPIO91__FUNC_GPIO91>;
			slew-rate = <1>;
			output-low;
		};
	};
};
&consys {
	pinctrl-names = "default", "gps_lna_state_init",
		"gps_lna_state_oh", "gps_lna_state_ol";
	pinctrl-0 = <&consys_pins_default>;
	pinctrl-1 = <&gpslna_pins_init>;
	pinctrl-2 = <&gpslna_pins_oh>;
	pinctrl-3 = <&gpslna_pins_ol>;
	status = "okay";
};
/* CONSYS end */

/* accdet start */
&accdet {
	accdet-mic-vol = <6>;
	headset-mode-setting = <0x500 0x500 1 0x1f0 0x800 0x800 0x20 0x44>;
	accdet-plugout-debounce = <16>;
	accdet-mic-mode = <1>;
	headset-eint-level-pol = <8>;
	headset-three-key-threshold = <0 90 210 430>;
	headset-three-key-threshold-CDD = <0 121 192 600>;
	headset-four-key-threshold = <0 58 121 192 400>;
	pinctrl-names = "default", "state_eint_as_int","state_eint_r_as_int";
	pinctrl-0 = <&accdet_pins_default>;
	pinctrl-1 = <&accdet_pins_eint_as_int>;
	pinctrl-2 = <&ACCDET_pins_eint_r_int>;
	status = "okay";
};
&pio {
	accdet_pins_default: accdetdefault {
	};
	accdet_pins_eint_as_int: accdeteint@0 {
		pins_cmd_dat {
			pinmux = <PINMUX_GPIO4__FUNC_GPIO4>;
			slew-rate = <0>;
			bias-disable;
		};
	};
	ACCDET_pins_eint_r_int:eint_hphr@0{
			pins_cmd_dat {
				pinmux = <PINMUX_GPIO3__FUNC_GPIO3>;
				slew-rate = <0>;
				bias-disable;
			};
	};
};
/* accdet end */


/* FINGERPRINT start */
&spi0 {
	#address-cells = <1>;
	#size-cells = <0>;
	fingerprint@0 {
		compatible = "goodix,goodix-fp";
		reg = <0>;
		spi-max-frequency = <8000000>;
		netlink-event = <30>;
		vfp-supply = <&mt_pmic_vcama_ldo_reg>;
		status = "okay";
	};
};

&goodix_fp {
	pinctrl-names = "fingerprint_irq", "miso_spi", "miso_pullhigh", "miso_pulllow", "reset_high", "reset_low","mosi_spi","mosi_pullhigh","mosi_pulllow","cs_spi","cs_pullhigh","cs_pulllow","clk_spi","clk_pullhigh","clk_pulllow";
	pinctrl-0 = <&fingerprint_irq>;
	pinctrl-1 = <&fingerprint_miso_spi>;
	pinctrl-2 = <&fingerprint_miso_pullhigh>;
	pinctrl-3 = <&fingerprint_miso_pulllow>;
	pinctrl-4 = <&fingerprint_reset_high>;
	pinctrl-5 = <&fingerprint_reset_low>;
	pinctrl-6 = <&fingerprint_mosi_spi>;
	pinctrl-7 = <&fingerprint_mosi_pullhigh>;
	pinctrl-8 = <&fingerprint_mosi_pulllow>;
	pinctrl-9 = <&fingerprint_cs_spi>;
	pinctrl-10 = <&fingerprint_cs_pullhigh>;
	pinctrl-11 = <&fingerprint_cs_pulllow>;
	pinctrl-12 = <&fingerprint_clk_spi>;
	pinctrl-13 = <&fingerprint_clk_pullhigh>;
	pinctrl-14 = <&fingerprint_clk_pulllow>;
	status = "okay";
};

&pio {
	fingerprint_irq: state_irq {
		pins_cmd_dat {
			pinmux = <PINMUX_GPIO5__FUNC_GPIO5>;
			slew-rate = <0>;
			bias-disable;
		};
	};

	fingerprint_miso_spi: state_miso_spi {
		pins_cmd_dat {
			pinmux = <PINMUX_GPIO155__FUNC_SPI0_MI>;
		};
	};

	fingerprint_miso_pullhigh: state_miso_pullhigh {
		pins_cmd_dat {
			pinmux = <PINMUX_GPIO155__FUNC_GPIO155>;
			slew-rate = <1>;
			output-high;
		};
	};

	fingerprint_miso_pulllow: state_miso_pulllow {
		pins_cmd_dat {
			pinmux = <PINMUX_GPIO155__FUNC_GPIO155>;
			slew-rate = <1>;
			output-low;
		};
	};

	fingerprint_reset_high: state_reset_high {
		pins_cmd_dat {
			pinmux = <PINMUX_GPIO169__FUNC_GPIO169>;
			slew-rate = <1>;
			output-high;
		};
	};

	fingerprint_reset_low: state_reset_low {
		pins_cmd_dat {
			pinmux = <PINMUX_GPIO169__FUNC_GPIO169>;
			slew-rate = <1>;
			output-low;
		};
	};
	
	fingerprint_mosi_spi: state_mosi_spi {
		pins_cmd_dat {
			pinmux = <PINMUX_GPIO157__FUNC_SPI0_MO>;
		};
	};
	fingerprint_mosi_pullhigh: state_mosi_pullhigh {
		pins_cmd_dat {
			pinmux = <PINMUX_GPIO157__FUNC_GPIO157>;
			slew-rate = <1>;
			output-high;
		};
	};

	fingerprint_mosi_pulllow: state_mosi_pulllow {
		pins_cmd_dat {
			pinmux = <PINMUX_GPIO157__FUNC_GPIO157>;
			slew-rate = <1>;
			output-low;
		};
	};
	fingerprint_cs_spi: state_cs_spi {
		pins_cmd_dat {
			pinmux = <PINMUX_GPIO156__FUNC_SPI0_CSB>;
		};
	};
	
	fingerprint_cs_pullhigh: state_cs_pullhigh {
		pins_cmd_dat {
			pinmux = <PINMUX_GPIO156__FUNC_GPIO156>;
			slew-rate = <1>;
			output-high;
		};
	};

	fingerprint_cs_pulllow: state_cs_pulllow {
		pins_cmd_dat {
			pinmux = <PINMUX_GPIO156__FUNC_GPIO156>;
			slew-rate = <1>;
			output-low;
		};
	};
	
	fingerprint_clk_spi: state_clk_spi {
		pins_cmd_dat {
			pinmux = <PINMUX_GPIO158__FUNC_SPI0_CLK>;
		};
	};
	fingerprint_clk_pullhigh: state_clk_pullhigh {
		pins_cmd_dat {
			pinmux = <PINMUX_GPIO158__FUNC_GPIO158>;
			slew-rate = <1>;
			output-high;
		};
	};

	fingerprint_clk_pulllow: state_clk_pulllow {
		pins_cmd_dat {
			pinmux = <PINMUX_GPIO158__FUNC_GPIO158>;
			slew-rate = <1>;
			output-low;
		};
	};
	
	
};
/* FINGERPRINT end */

/* battery end */
&bat_gm30 {
	EMBEDDED_SEL = <(0)>;
};
/* battery end */

// add for fingerprint id detect start
&pio {
	fp_id_detect: fp_id_detect {
		pins_cmd0_dat {
			pinmux = <PINMUX_GPIO170__FUNC_GPIO170>;
			slew-rate = <0>;
			bias-pull-up = <11>;
		};
	};
};
&fp_id {
	status="okay";
	pinctrl-names = "default";
	vivo,project-name = "PD1803";
	pinctrl-0 = <&fp_id_detect>;
	fp_id,gpios= <&pio 170 0>;
};
// add for fingerprint id detect end

/* IRTX GPIO end */
&irtx_pwm {
	pinctrl-names = "irtx_gpio_led_default", "irtx_gpio_led_set";
	pinctrl-0 = <&irtx_gpio_led_default>;
	pinctrl-1 = <&irtx_gpio_led_set>;
	status = "okay";
};
&pio {
	irtx_gpio_led_default:irtx_gpio_led_def@gpio90 {
		pins_cmd_dat {
			pinmux = <PINMUX_GPIO90__FUNC_GPIO90>;
			slew-rate = <1>;
			bias-disable;
			output-low;
			input-schmitt-enable = <0>;
		};
	};

	irtx_gpio_led_set:irtx_gpio_led_set@gpio90 {
		pins_cmd_dat {
			pinmux = <PINMUX_GPIO90__FUNC_PWM0>;
			slew-rate = <1>;
			output-high;
		};
	};
};
/* IRTX GPIO Settings -End */

/* AUDIO GPIO standardization */
&audgpio {
	pinctrl-names = "aud_clk_mosi_off",
			"aud_clk_mosi_on",
			"aud_clk_miso_off",
			"aud_clk_miso_on",
			"aud_dat_mosi_off",
			"aud_dat_mosi_on",
			"aud_dat_miso_off",
			"aud_dat_miso_on",
			"aud_smartpa_off",
			"aud_smartpa_on";
	pinctrl-0 = <&aud_clk_mosi_off>;
	pinctrl-1 = <&aud_clk_mosi_on>;
	pinctrl-2 = <&aud_clk_miso_off>;
	pinctrl-3 = <&aud_clk_miso_on>;
	pinctrl-4 = <&aud_dat_mosi_off>;
	pinctrl-5 = <&aud_dat_mosi_on>;
	pinctrl-6 = <&aud_dat_miso_off>;
	pinctrl-7 = <&aud_dat_miso_on>;
	pinctrl-8 = <&aud_pins_smartpa_off>;
	pinctrl-9 = <&aud_pins_smartpa_on>;
	status = "okay";
};

&pio {
	aud_clk_mosi_off: aud_clk_mosi_off {
		pins_cmd0_dat {
			pinmux = <PINMUX_GPIO136__FUNC_GPIO136>;
		};
	};

	aud_clk_mosi_on: aud_clk_mosi_on {
		pins_cmd0_dat {
			pinmux = <PINMUX_GPIO136__FUNC_AUD_CLK_MOSI>;
		};
	};

	aud_clk_miso_off: aud_clk_miso_off {
		pins_cmd0_dat {
			pinmux = <PINMUX_GPIO140__FUNC_GPIO140>;
		};
	};

	aud_clk_miso_on: aud_clk_miso_on {
		pins_cmd0_dat {
			pinmux = <PINMUX_GPIO140__FUNC_AUD_CLK_MISO>;
		};
	};

	aud_dat_mosi_off: aud_dat_mosi_off {
		pins_cmd1_dat {
			pinmux = <PINMUX_GPIO138__FUNC_GPIO138>;
			input-enable;
			slew-rate = <0>;
			bias-disable;
		};
		pins_cmd2_dat {
			pinmux = <PINMUX_GPIO139__FUNC_GPIO139>;
			input-enable;
			slew-rate = <0>;
			bias-disable;
		};
	};

	aud_dat_mosi_on: aud_dat_mosi_on {
		pins_cmd1_dat {
			pinmux = <PINMUX_GPIO138__FUNC_AUD_DAT_MOSI0>;
		};
		pins_cmd2_dat {
			pinmux = <PINMUX_GPIO139__FUNC_AUD_DAT_MOSI1>;
		};
	};

	aud_dat_miso_off: aud_dat_miso_off {
		pins_cmd1_dat {
			pinmux = <PINMUX_GPIO142__FUNC_GPIO142>;
			input-enable;
			slew-rate = <0>;
			bias-disable;
		};
		pins_cmd2_dat {
			pinmux = <PINMUX_GPIO143__FUNC_GPIO143>;
			input-enable;
			slew-rate = <0>;
			bias-disable;
		};
	};

	aud_dat_miso_on: aud_dat_miso_on {
		pins_cmd1_dat {
			pinmux = <PINMUX_GPIO142__FUNC_AUD_DAT_MISO0>;
		};
		pins_cmd2_dat {
			pinmux = <PINMUX_GPIO143__FUNC_AUD_DAT_MISO1>;
		};
	};

	aud_pins_smartpa_off: aud_pins_smartpa_off {
		pins_cmd0_dat {
			pinmux = <PINMUX_GPIO17__FUNC_GPIO17>;
		};
		pins_cmd1_dat {
			pinmux = <PINMUX_GPIO18__FUNC_GPIO18>;
		};
		pins_cmd2_dat {
			pinmux = <PINMUX_GPIO19__FUNC_GPIO19>;
		};
		pins_cmd3_dat {
			pinmux = <PINMUX_GPIO20__FUNC_GPIO20>;
		};
	};

	aud_pins_smartpa_on: aud_pins_smartpa_on {
		pins_cmd0_dat {
			pinmux = <PINMUX_GPIO17__FUNC_I2S0_DI>;
		};
		pins_cmd1_dat {
			pinmux = <PINMUX_GPIO18__FUNC_I2S3_BCK>;
		};
		pins_cmd2_dat {
			pinmux = <PINMUX_GPIO19__FUNC_I2S3_LRCK>;
		};
		pins_cmd3_dat {
			pinmux = <PINMUX_GPIO20__FUNC_I2S3_DO>;
		};
	};
};
/* AUDIO end */

&mt6370_pmu {
	mt6370,intr_gpio_num = <11>; /* direct defined GPIO num */
	mt6370,intr_gpio = <&pio 11 0x0>;
};

&mt6370_typec {
	mt6370pd,intr_gpio_num = <41>; /* direct defined GPIO num */
	mt6370pd,intr_gpio = <&pio 41 0x0>;
};

&charger {
	algorithm_name = "DualSwitchCharging";
	chg1_ta_ac_charger_current = <2000000>;
	chg2_ta_ac_charger_current = <2000000>;
};

&i2c3 {
	rt9465@4b {
		compatible = "richtek,rt9465";
		reg = <0x4b>;
		status = "okay";
		rt,en_gpio_num = <176>;
		rt,en_gpio = <&pio 176 0x0>;
		rt,intr_gpio_num = <23>; /* direct defined GPIO num */
		rt,intr_gpio = <&pio 23 0x0>;
		interrupt-names = "wdtmri";
		charger_name = "secondary_chg";
		ichg = <1500000>; /* uA */
		mivr = <4500000>; /* uV */
		cv = <4550000>; /* uV */
		ieoc = <700000>; /* uA */
		safety_timer = <12>; /* hour */
		en_st; /* safety timer */
		/* en_te; */
		en_wdt;
	};
};

&pio {
	camera_pins_cam0_mclk_on: camera_pins_cam0_mclk_on {
		pins_cmd_dat {
			pinmux = <PINMUX_GPIO99__FUNC_CMMCLK0>;
		};
	};
	camera_pins_cam0_mclk_off: camera_pins_cam0_mclk_off {
		pins_cmd_dat {
			pinmux = <PINMUX_GPIO99__FUNC_GPIO99>;
		};
	};
	camera_pins_cam1_mclk_on: camera_pins_cam1_mclk_on {
		pins_cmd_dat {
			pinmux = <PINMUX_GPIO100__FUNC_CMMCLK1>;
		};
	};
	camera_pins_cam1_mclk_off: camera_pins_cam1_mclk_off {
		pins_cmd_dat {
			pinmux = <PINMUX_GPIO100__FUNC_GPIO100>;
		};
	};
	camera_pins_cam2_mclk_on: camera_pins_cam2_mclk_on {
		pins_cmd_dat {
			pinmux = <PINMUX_GPIO108__FUNC_CMMCLK2>;
		};
	};
	camera_pins_cam2_mclk_off: camera_pins_cam2_mclk_off {
		pins_cmd_dat {
			pinmux = <PINMUX_GPIO108__FUNC_GPIO108>;
		};
	};
/* cam 0 main start*/
	camera_pins_cam0_rst0: cam0@0 {
		pins_cmd_dat {
			pinmux = <PINMUX_GPIO101__FUNC_GPIO101>;
			slew-rate = <1>;
			output-low;
		};
	};
	camera_pins_cam0_rst1: cam0@1 {
		pins_cmd_dat {
			pinmux = <PINMUX_GPIO101__FUNC_GPIO101>;
			slew-rate = <1>;
			output-high;
		};
	};
/*
	camera_pins_cam_ldo_rear_vcamd_0: cam0@vcamd0 {
		pins_cmd_dat {
			pinmux = <PINMUX_GPIO98__FUNC_GPIO98>;
			slew-rate = <1>;
			output-low;
		};
	};
	camera_pins_cam_ldo_rear_vcamd_1: cam0@vcamd1 {
		pins_cmd_dat {
			pinmux = <PINMUX_GPIO98__FUNC_GPIO98>;
			slew-rate = <1>;
			output-high;
		};
	};
*/	
	camera_pins_cam_ldo_rear_vcama_0: cam0@vcama0 {
		pins_cmd_dat {
			pinmux = <PINMUX_GPIO97__FUNC_GPIO97>;
			slew-rate = <1>;
			output-low;
		};
	};
	camera_pins_cam_ldo_rear_vcama_1: cam0@vcama1 {
		pins_cmd_dat {
			pinmux = <PINMUX_GPIO97__FUNC_GPIO97>;
			slew-rate = <1>;
			output-high;
		};
	};
/* cam 0 main end*/

/* cam 1 sub start*/
	camera_pins_cam1_rst0: cam1@0 {
		pins_cmd_dat {
			pinmux = <PINMUX_GPIO109__FUNC_GPIO109>;
			slew-rate = <1>;
			output-low;
		};
	};
	camera_pins_cam1_rst1: cam1@1 {
		pins_cmd_dat {
			pinmux = <PINMUX_GPIO109__FUNC_GPIO109>;
			slew-rate = <1>;
			output-high;
		};
	};
	camera_pins_cam_ldo_sub_vcama_0: cam1@vcama0 {
		pins_cmd_dat {
			pinmux = <PINMUX_GPIO107__FUNC_GPIO107>;
			slew-rate = <1>;
			output-low;
		};
	};
	camera_pins_cam_ldo_sub_vcama_1: cam1@vcama1 {
		pins_cmd_dat {
			pinmux = <PINMUX_GPIO107__FUNC_GPIO107>;
			slew-rate = <1>;
			output-high;
		};
	};
/* cam 1 sub end*/

/* cam 2 main2 start*/
	camera_pins_cam2_rst0: cam2@0 {
		pins_cmd_dat {
			pinmux = <PINMUX_GPIO102__FUNC_GPIO102>;
			slew-rate = <1>;
			output-low;
		};
	};
	camera_pins_cam2_rst1: cam2@1 {
		pins_cmd_dat {
			pinmux = <PINMUX_GPIO102__FUNC_GPIO102>;
			slew-rate = <1>;
			output-high;
		};
	};
	camera_pins_cam_ldo_rear2_vcama_0: cam2@vcama0 {
		pins_cmd_dat {
			pinmux = <PINMUX_GPIO107__FUNC_GPIO107>;
			slew-rate = <1>;
			output-low;
		};
	};
	camera_pins_cam_ldo_rear2_vcama_1: cam2@vcama1 {
		pins_cmd_dat {
			pinmux = <PINMUX_GPIO107__FUNC_GPIO107>;
			slew-rate = <1>;
			output-high;
		};
	};
/* cam 2 main2 end*/

	camera_pins_default: camdefault {
	};

};

&kd_camera_hw1 {
	pinctrl-names = "default",
			"cam0_rst0",
			"cam0_rst1",
			"cam1_rst0",
			"cam1_rst1",
			"cam2_rst0",
			"cam2_rst1",
			/*"cam0_vcamd_on",*/
			/*"cam0_vcamd_off",*/
			"cam0_vcama_on",
			"cam0_vcama_off",
			"cam1_vcama_on",
			"cam1_vcama_off",
			"cam2_vcama_on",
			"cam2_vcama_off",
			"cam0_mclk_on",
			"cam0_mclk_off",
			"cam1_mclk_on",
			"cam1_mclk_off",
			"cam2_mclk_on",
			"cam2_mclk_off";

	pinctrl-0 = <&camera_pins_default>;
	pinctrl-1 = <&camera_pins_cam0_rst0>;
	pinctrl-2 = <&camera_pins_cam0_rst1>;
	pinctrl-3 = <&camera_pins_cam1_rst0>;
	pinctrl-4 = <&camera_pins_cam1_rst1>;
	pinctrl-5 = <&camera_pins_cam2_rst0>;
	pinctrl-6 = <&camera_pins_cam2_rst1>;
	/*pinctrl-7 = <&camera_pins_cam_ldo_rear_vcamd_1>;*/
	/*pinctrl-8 = <&camera_pins_cam_ldo_rear_vcamd_0>;*/
	pinctrl-7 = <&camera_pins_cam_ldo_rear_vcama_1>;
	pinctrl-8 = <&camera_pins_cam_ldo_rear_vcama_0>;
	pinctrl-9 = <&camera_pins_cam_ldo_sub_vcama_1>;
	pinctrl-10 = <&camera_pins_cam_ldo_sub_vcama_0>;
	pinctrl-11 = <&camera_pins_cam_ldo_rear2_vcama_1>;
	pinctrl-12 = <&camera_pins_cam_ldo_rear2_vcama_0>;
	pinctrl-13 = <&camera_pins_cam0_mclk_on>;
	pinctrl-14 = <&camera_pins_cam0_mclk_off>;
	pinctrl-15 = <&camera_pins_cam2_mclk_on>;
	pinctrl-16 = <&camera_pins_cam2_mclk_off>;
	pinctrl-17 = <&camera_pins_cam1_mclk_on>;
	pinctrl-18 = <&camera_pins_cam1_mclk_off>;
	gpio98 = <&pio 98 0>;
	status = "okay";

};

/* FLASHLIGHT START*/
&pio {
	flashlights_lm3644_pins_default: flashlight_default {
	};
	
	flashlights_lm3644_pins_hwen_high: hwen_high {
		pins_cmd_dat {
			pinmux = <PINMUX_GPIO153__FUNC_GPIO153>;
			slew-rate = <1>;
			output-high;
		};
	};
	
	flashlights_lm3644_pins_hwen_low: hwen_low {
		pins_cmd_dat {
			pinmux = <PINMUX_GPIO153__FUNC_GPIO153>;
			slew-rate = <1>;
			output-low;
		};
	};
	
};

&flashlights_lm3644 {
	pinctrl-names = "default", "hwen_high", "hwen_low";
	pinctrl-0 = <&flashlights_lm3644_pins_default>;
	pinctrl-1 = <&flashlights_lm3644_pins_hwen_high>;
	pinctrl-2 = <&flashlights_lm3644_pins_hwen_low>;
	status = "okay";
};
/* FLASHLIGHT END*/

&i2c6 {
	#address-cells = <1>;
	#size-cells = <0>;
	clock-frequency = <400000>;
	mediatek,use-open-drain;
	lm3697_i2c@36 {
		compatible = "lm3697_i2c";
		reg = <0x36>;
		status = "okay";
	};
};
/*
	ktd2151@3e {
		compatible = "mediatek,ktd2151";
		reg = <0x3e>;
		status = "okay";
	};
*/
/***************for LCM GPIO config begin****************/

&mtkfb {
	pinctrl-names = "lcm_rst_out0_gpio", 
					"lcm_rst_out1_gpio",
					"lcm_vddi_en0_gpio", 
					"lcm_vddi_en1_gpio",
					"lcm_enp_en0_gpio", 
					"lcm_enp_en1_gpio",
					"lcm_enn_en0_gpio", 
					"lcm_enn_en1_gpio",
					"lcm_bkg_en0_gpio", 
					"lcm_bkg_en1_gpio",
					"tp_rst_out0_gpio",
					"tp_rst_out1_gpio";

	pinctrl-0 = <&lcm_rst_out0_gpio>;
	pinctrl-1 = <&lcm_rst_out1_gpio>;

	pinctrl-2 = <&lcm_vddi_en0_gpio>;
	pinctrl-3 = <&lcm_vddi_en1_gpio>;

	pinctrl-4 = <&lcm_enp_en0_gpio>;
	pinctrl-5 = <&lcm_enp_en1_gpio>;

	pinctrl-6 = <&lcm_enn_en0_gpio>;
	pinctrl-7 = <&lcm_enn_en1_gpio>;

	pinctrl-8 = <&lcm_bkg_en0_gpio>;
	pinctrl-9 = <&lcm_bkg_en1_gpio>;

	pinctrl-10 = <&tp_rst_out0_gpio>;
	pinctrl-11 = <&tp_rst_out1_gpio>;

	status = "okay";
};
&pio {
	lcm_rst_out0_gpio: lcm_rst_out0_gpio {
		pins_cmd_dat {
			pinmux = <PINMUX_GPIO45__FUNC_GPIO45>;
			slew-rate = <1>;
			output-low;
		};
	};
	lcm_rst_out1_gpio: lcm_rst_out1_gpio {
		pins_cmd_dat {
			pinmux = <PINMUX_GPIO45__FUNC_GPIO45>;
			slew-rate = <1>;
			output-high;
		};
	};
	lcm_vddi_en0_gpio: lcm_vddi_en0_gpio {
		pins_cmd_dat {
			pinmux = <PINMUX_GPIO166__FUNC_GPIO166>;
			slew-rate = <1>;
			output-low;
		};
	};
	lcm_vddi_en1_gpio: lcm_vddi_en1_gpio {
		pins_cmd_dat {
			pinmux = <PINMUX_GPIO166__FUNC_GPIO166>;
			slew-rate = <1>;
			output-high;
		};
	};

	lcm_enp_en0_gpio: lcm_enp_en0_gpio {
		pins_cmd_dat {
			pinmux = <PINMUX_GPIO152__FUNC_GPIO152>;
			slew-rate = <1>;
			output-low;
		};
	};
	lcm_enp_en1_gpio: lcm_enp_en1_gpio {
		pins_cmd_dat {
			pinmux = <PINMUX_GPIO152__FUNC_GPIO152>;
			slew-rate = <1>;
			output-high;
		};
	};

	lcm_enn_en0_gpio: lcm_enn_en0_gpio {
		pins_cmd_dat {
			pinmux = <PINMUX_GPIO151__FUNC_GPIO151>;
			slew-rate = <1>;
			output-low;
		};
	};
	lcm_enn_en1_gpio: lcm_enn_en1_gpio {
		pins_cmd_dat {
			pinmux = <PINMUX_GPIO151__FUNC_GPIO151>;
			slew-rate = <1>;
			output-high;
		};
	};

	lcm_bkg_en0_gpio: lcm_bkg_en0_gpio {
		pins_cmd_dat {
			pinmux = <PINMUX_GPIO150__FUNC_GPIO150>;
			slew-rate = <1>;
			output-low;
		};
	};
	lcm_bkg_en1_gpio: lcm_bkg_en1_gpio {
		pins_cmd_dat {
			pinmux = <PINMUX_GPIO150__FUNC_GPIO150>;
			slew-rate = <1>;
			output-high;
		};
	};
	tp_rst_out0_gpio: tp_rst_out0_gpio {
		pins_cmd_dat {
			pinmux = <PINMUX_GPIO10__FUNC_GPIO10>;
			slew-rate = <1>;
			output-low;
		};
	};
	tp_rst_out1_gpio: tp_rst_out1_gpio {
		pins_cmd_dat {
			pinmux = <PINMUX_GPIO10__FUNC_GPIO10>;
			slew-rate = <1>;
			output-high;
		};
	};
};
/************************************/
/***************for LCM GPIO config end****************/

&boards_version {
	pinctrl-names = "default";
	pinctrl-0 = <&board_version>;
	gpio_nums = <7>;
	gpios = <171 172 173 174 175 176 177>;
	gpios_start = <&pio 171 0>;
};

&tcard_sim_slot {	
		pinctrl-names = "default";
		pinctrl-0 = <&card_detect>;
        factory-test,sim1-card;
        factory-test,sim2-card;
		factory-test,tf-card;
		vivo,new_card_detect;
        card-detect-sim1,gpios = <&pio 47 0x0>;
        card-detect-sim2,gpios = <&pio 47 0x0>;
		card-detect-tf-card,gpios = <&pio 1 0x0>;	
};

&pio {
	board_version: hardware_board_version {
		pins_cmd0_dat {
			pinmux = <PINMUX_GPIO171__FUNC_GPIO171>;
			slew-rate = <0>;
			bias-pull-up = <11>;
		};
		pins_cmd1_dat {
			pinmux = <PINMUX_GPIO172__FUNC_GPIO172>;
			slew-rate = <0>;
			bias-pull-up = <11>;
		};
		pins_cmd2_dat {
			pinmux = <PINMUX_GPIO173__FUNC_GPIO173>;
			slew-rate = <0>;
			bias-pull-up = <11>;
		};
		pins_cmd3_dat {
			pinmux = <PINMUX_GPIO174__FUNC_GPIO174>;
			slew-rate = <0>;
			bias-pull-up = <11>;
		};		
		pins_cmd4_dat {
			pinmux = <PINMUX_GPIO175__FUNC_GPIO175>;
			slew-rate = <0>;
			bias-pull-up = <11>;
		};
		pins_cmd5_dat {
			pinmux = <PINMUX_GPIO176__FUNC_GPIO176>;
			slew-rate = <0>;
			bias-pull-up = <11>;
		};
		pins_cmd6_dat {
			pinmux = <PINMUX_GPIO177__FUNC_GPIO177>;
			slew-rate = <0>;
			bias-pull-up = <11>;
		};		
	};
	
	card_detect: card_sim_detect {
		pins_cmd0_dat {
			pinmux = <PINMUX_GPIO47__FUNC_MD_INT1_C2K_UIM0_HOT_PLUG>;
			slew-rate = <0>;
			bias-disable;
		};
		pins_cmd1_dat {
			pinmux = <PINMUX_GPIO46__FUNC_GPIO46>;
			slew-rate = <0>;
			bias-disable;
		};		
		pins_cmd2_dat {
			pinmux = <PINMUX_GPIO1__FUNC_GPIO1>;
			slew-rate = <0>;
			bias-disable;
		};
	};
};


#include "cust_vivo_PD1803.dtsi"
#include "vivo_soc_codec.dtsi"
/*End of this file, DO NOT ADD ANYTHING HERE*/
